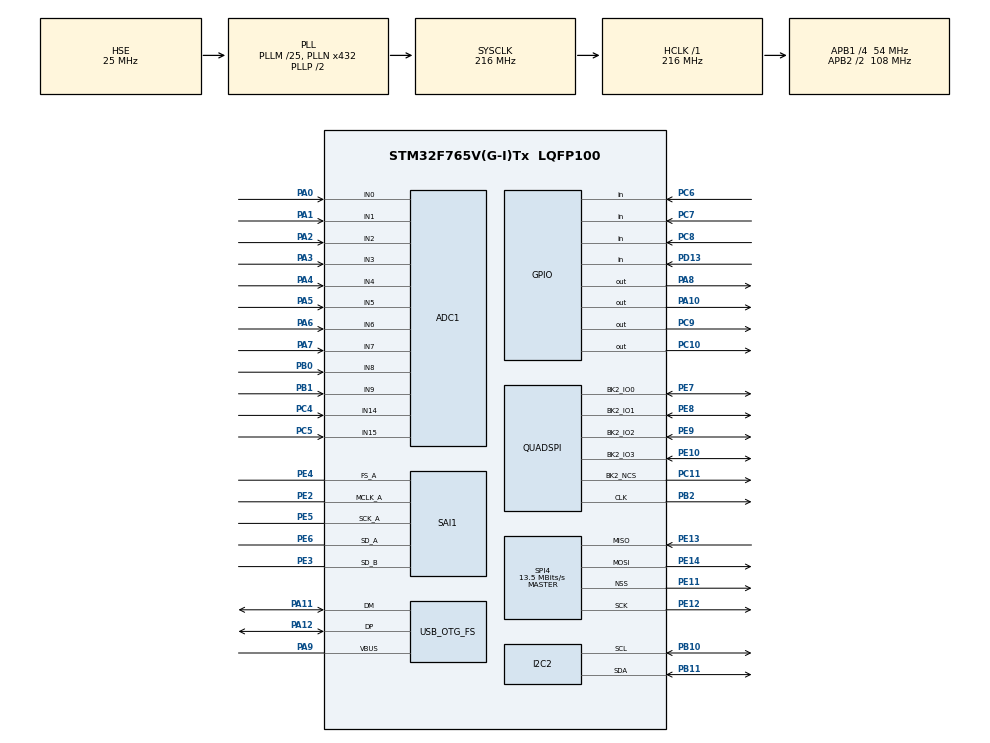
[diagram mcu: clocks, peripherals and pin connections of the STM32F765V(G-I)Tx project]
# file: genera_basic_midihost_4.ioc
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ADC1.Channel-0\#ChannelRegularConversion=ADC_CHANNEL_9
ADC1.Channel-1\#ChannelRegularConversion=ADC_CHANNEL_8
ADC1.Channel-10\#ChannelRegularConversion=ADC_CHANNEL_3
ADC1.Channel-11\#ChannelRegularConversion=ADC_CHANNEL_2
ADC1.Channel-2\#ChannelRegularConversion=ADC_CHANNEL_15
ADC1.Channel-3\#ChannelRegularConversion=ADC_CHANNEL_14
ADC1.Channel-4\#ChannelRegularConversion=ADC_CHANNEL_1
ADC1.Channel-5\#ChannelRegularConversion=ADC_CHANNEL_0
ADC1.Channel-6\#ChannelRegularConversion=ADC_CHANNEL_5
ADC1.Channel-7\#ChannelRegularConversion=ADC_CHANNEL_4
ADC1.Channel-8\#ChannelRegularConversion=ADC_CHANNEL_7
ADC1.Channel-9\#ChannelRegularConversion=ADC_CHANNEL_6
ADC1.ContinuousConvMode=ENABLE
ADC1.ExternalTrigConv=ADC_EXTERNALTRIGCONV_T1_CC1
ADC1.NbrOfConversion=12
ADC1.NbrOfConversionFlag=1
ADC1.Rank-0\#ChannelRegularConversion=1
ADC1.Rank-1\#ChannelRegularConversion=2
ADC1.Rank-10\#ChannelRegularConversion=11
ADC1.Rank-11\#ChannelRegularConversion=12
ADC1.Rank-2\#ChannelRegularConversion=3
ADC1.Rank-3\#ChannelRegularConversion=4
ADC1.Rank-4\#ChannelRegularConversion=5
ADC1.Rank-5\#ChannelRegularConversion=6
ADC1.Rank-6\#ChannelRegularConversion=7
ADC1.Rank-7\#ChannelRegularConversion=8
ADC1.Rank-8\#ChannelRegularConversion=9
ADC1.Rank-9\#ChannelRegularConversion=10
ADC1.SamplingTime-0\#ChannelRegularConversion=ADC_SAMPLETIME_3CYCLES
ADC1.SamplingTime-1\#ChannelRegularConversion=ADC_SAMPLETIME_3CYCLES
ADC1.SamplingTime-10\#ChannelRegularConversion=ADC_SAMPLETIME_3CYCLES
ADC1.SamplingTime-11\#ChannelRegularConversion=ADC_SAMPLETIME_3CYCLES
ADC1.SamplingTime-2\#ChannelRegularConversion=ADC_SAMPLETIME_3CYCLES
ADC1.SamplingTime-3\#ChannelRegularConversion=ADC_SAMPLETIME_3CYCLES
ADC1.SamplingTime-4\#ChannelRegularConversion=ADC_SAMPLETIME_3CYCLES
ADC1.SamplingTime-5\#ChannelRegularConversion=ADC_SAMPLETIME_3CYCLES
ADC1.SamplingTime-6\#ChannelRegularConversion=ADC_SAMPLETIME_3CYCLES
ADC1.SamplingTime-7\#ChannelRegularConversion=ADC_SAMPLETIME_3CYCLES
ADC1.SamplingTime-8\#ChannelRegularConversion=ADC_SAMPLETIME_3CYCLES
ADC1.SamplingTime-9\#ChannelRegularConversion=ADC_SAMPLETIME_3CYCLES
ADC1.master=1
Dma.ADC1.4.Direction=DMA_PERIPH_TO_MEMORY
Dma.ADC1.4.FIFOMode=DMA_FIFOMODE_DISABLE
Dma.ADC1.4.Instance=DMA2_Stream4
Dma.ADC1.4.MemDataAlignment=DMA_MDATAALIGN_HALFWORD
Dma.ADC1.4.MemInc=DMA_MINC_ENABLE
Dma.ADC1.4.Mode=DMA_NORMAL
Dma.ADC1.4.PeriphDataAlignment=DMA_PDATAALIGN_HALFWORD
Dma.ADC1.4.PeriphInc=DMA_PINC_DISABLE
Dma.ADC1.4.Priority=DMA_PRIORITY_LOW
Dma.I2C2_RX.2.Direction=DMA_PERIPH_TO_MEMORY
Dma.I2C2_RX.2.FIFOMode=DMA_FIFOMODE_DISABLE
Dma.I2C2_RX.2.Instance=DMA1_Stream2
Dma.I2C2_RX.2.MemDataAlignment=DMA_MDATAALIGN_BYTE
Dma.I2C2_RX.2.MemInc=DMA_MINC_ENABLE
Dma.I2C2_RX.2.Mode=DMA_NORMAL
Dma.I2C2_RX.2.PeriphDataAlignment=DMA_PDATAALIGN_BYTE
Dma.I2C2_RX.2.PeriphInc=DMA_PINC_DISABLE
Dma.I2C2_RX.2.Priority=DMA_PRIORITY_LOW
Dma.I2C2_TX.3.Direction=DMA_MEMORY_TO_PERIPH
Dma.I2C2_TX.3.FIFOMode=DMA_FIFOMODE_DISABLE
Dma.I2C2_TX.3.Instance=DMA1_Stream4
Dma.I2C2_TX.3.MemDataAlignment=DMA_MDATAALIGN_BYTE
Dma.I2C2_TX.3.MemInc=DMA_MINC_ENABLE
Dma.I2C2_TX.3.Mode=DMA_NORMAL
Dma.I2C2_TX.3.PeriphDataAlignment=DMA_PDATAALIGN_BYTE
Dma.I2C2_TX.3.PeriphInc=DMA_PINC_DISABLE
Dma.I2C2_TX.3.Priority=DMA_PRIORITY_LOW
Dma.Request0=SAI1_A
Dma.Request1=SAI1_B
Dma.Request2=I2C2_RX
Dma.Request3=I2C2_TX
Dma.Request4=ADC1
Dma.SAI1_A.0.Direction=DMA_MEMORY_TO_PERIPH
Dma.SAI1_A.0.FIFOMode=DMA_FIFOMODE_ENABLE
Dma.SAI1_A.0.FIFOThreshold=DMA_FIFO_THRESHOLD_FULL
Dma.SAI1_A.0.Instance=DMA2_Stream1
Dma.SAI1_A.0.MemBurst=DMA_MBURST_SINGLE
Dma.SAI1_A.0.MemDataAlignment=DMA_MDATAALIGN_HALFWORD
Dma.SAI1_A.0.MemInc=DMA_MINC_ENABLE
Dma.SAI1_A.0.Mode=DMA_CIRCULAR
Dma.SAI1_A.0.PeriphBurst=DMA_PBURST_SINGLE
Dma.SAI1_A.0.PeriphDataAlignment=DMA_PDATAALIGN_HALFWORD
Dma.SAI1_A.0.PeriphInc=DMA_PINC_DISABLE
Dma.SAI1_A.0.Priority=DMA_PRIORITY_HIGH
Dma.SAI1_B.1.Direction=DMA_PERIPH_TO_MEMORY
Dma.SAI1_B.1.FIFOMode=DMA_FIFOMODE_ENABLE
Dma.SAI1_B.1.FIFOThreshold=DMA_FIFO_THRESHOLD_FULL
Dma.SAI1_B.1.Instance=DMA2_Stream0
Dma.SAI1_B.1.MemBurst=DMA_MBURST_SINGLE
Dma.SAI1_B.1.MemDataAlignment=DMA_MDATAALIGN_HALFWORD
Dma.SAI1_B.1.MemInc=DMA_MINC_ENABLE
Dma.SAI1_B.1.Mode=DMA_CIRCULAR
Dma.SAI1_B.1.PeriphBurst=DMA_PBURST_SINGLE
Dma.SAI1_B.1.PeriphDataAlignment=DMA_PDATAALIGN_HALFWORD
Dma.SAI1_B.1.PeriphInc=DMA_PINC_DISABLE
Dma.SAI1_B.1.Priority=DMA_PRIORITY_HIGH
I2C2.Timing=0x20404768
Mcu.Family=STM32F7
Mcu.Name=STM32F765V(G-I)Tx
Mcu.Package=LQFP100
NVIC.DMA1_Stream2_IRQn=true\:0\:0\:false\:false\:true
NVIC.DMA1_Stream4_IRQn=true\:0\:0\:false\:false\:true
NVIC.DMA2_Stream0_IRQn=true\:0\:0\:false\:false\:true
NVIC.DMA2_Stream1_IRQn=true\:0\:0\:false\:false\:true
NVIC.DMA2_Stream4_IRQn=true\:0\:0\:false\:false\:true
NVIC.OTG_FS_IRQn=true\:0\:0\:false\:false\:true
NVIC.PriorityGroup=NVIC_PRIORITYGROUP_4
PA0/WKUP.Signal=ADCx_IN0
PA1.Signal=ADCx_IN1
PA10.Signal=GPIO_Output
PA11.Mode=Host_Only
PA11.Signal=USB_OTG_FS_DM
PA12.Mode=Host_Only
PA12.Signal=USB_OTG_FS_DP
PA2.Signal=ADCx_IN2
PA3.Signal=ADCx_IN3
PA4.Signal=ADCx_IN4
PA5.Signal=ADCx_IN5
PA6.Signal=ADCx_IN6
PA7.Signal=ADCx_IN7
PA8.Signal=GPIO_Output
PA9.Mode=Activate_VBUS
PA9.Signal=USB_OTG_FS_VBUS
PB0.Signal=ADCx_IN8
PB1.Signal=ADCx_IN9
PB10.Mode=I2C
PB10.Signal=I2C2_SCL
PB11.Mode=I2C
PB11.Signal=I2C2_SDA
PB2.Mode=Single Bank 2
PB2.Signal=QUADSPI_CLK
PC10.Signal=GPIO_Output
PC11.Mode=Single Bank 2
PC11.Signal=QUADSPI_BK2_NCS
PC4.Signal=ADCx_IN14
PC5.Signal=ADCx_IN15
PC6.Signal=GPIO_Input
PC7.Signal=GPIO_Input
PC8.Signal=GPIO_Input
PC9.Signal=GPIO_Output
PD13.Signal=GPIO_Input
PE10.Mode=Single Bank 2
PE10.Signal=QUADSPI_BK2_IO3
PE11.Mode=NSS_Signal_Hard_Output
PE11.Signal=SPI4_NSS
PE12.Mode=Full_Duplex_Master
PE12.Signal=SPI4_SCK
PE13.Mode=Full_Duplex_Master
PE13.Signal=SPI4_MISO
PE14.Mode=Full_Duplex_Master
PE14.Signal=SPI4_MOSI
PE2.Mode=SAI_A_MasterWithClock
PE2.Signal=SAI1_MCLK_A
PE3.Mode=SAI_B_SyncSlave
PE3.Signal=SAI1_SD_B
PE4.Mode=SAI_A_MasterWithClock
PE4.Signal=SAI1_FS_A
PE5.Mode=SAI_A_MasterWithClock
PE5.Signal=SAI1_SCK_A
PE6.Mode=SAI_A_MasterWithClock
PE6.Signal=SAI1_SD_A
PE7.Mode=Single Bank 2
PE7.Signal=QUADSPI_BK2_IO0
PE8.Mode=Single Bank 2
PE8.Signal=QUADSPI_BK2_IO1
PE9.Mode=Single Bank 2
PE9.Signal=QUADSPI_BK2_IO2
PH0/OSC_IN.Mode=HSE-External-Oscillator
PH0/OSC_IN.Signal=RCC_OSC_IN
PH1/OSC_OUT.Mode=HSE-External-Oscillator
PH1/OSC_OUT.Signal=RCC_OSC_OUT
ProjectManager.HeapSize=0x200
ProjectManager.StackSize=0x400
ProjectManager.TargetToolchain=MDK-ARM V5
RCC.AHBFreq_Value=216000000
RCC.APB1CLKDivider=RCC_HCLK_DIV4
RCC.APB1Freq_Value=54000000
RCC.APB1TimFreq_Value=108000000
RCC.APB2CLKDivider=RCC_HCLK_DIV2
RCC.APB2Freq_Value=108000000
RCC.APB2TimFreq_Value=216000000
RCC.CortexFreq_Value=216000000
RCC.HCLKFreq_Value=216000000
RCC.HSE_VALUE=25000000
RCC.HSI_VALUE=16000000
RCC.LSE_VALUE=32768
RCC.PLLI2SN=344
RCC.PLLI2SQ=7
RCC.PLLM=25
RCC.PLLN=432
RCC.PLLQ=9
RCC.PLLSAIN=376
RCC.PLLSAIQ=9
RCC.SAI1CLockSelection=RCC_SAI1CLKSOURCE_PLLI2S
RCC.SYSCLKFreq_VALUE=216000000
RCC.SYSCLKSource=RCC_SYSCLKSOURCE_PLLCLK
RCC.USBFreq_Value=48000000
RCC.VCOOutputFreq_Value=432000000
SAI1.ErrorAudioFreq-SAI_A_MasterWithClock=-0.01 %
SAI1.InitProtocol-SAI_A_MasterWithClock=Enable
SAI1.InitProtocol-SAI_B_SyncSlave=Enable
SAI1.Instance-SAI_A_MasterWithClock=SAI$Index_Block_A
SAI1.Instance-SAI_B_SyncSlave=SAI$Index_Block_B
SAI1.MClockEnable=SAI_MASTERCLOCK_ENABLE
SAI1.RealAudioFreq-SAI_A_MasterWithClock=191.964 KHz
SAI1.Synchro-SAI_A_MasterWithClock=SAI_ASYNCHRONOUS
SAI1.Synchro-SAI_B_SyncSlave=SAI_SYNCHRONOUS
SAI1.VirtualMode-SAI_A_MasterWithClock=VM_MASTER
SAI1.VirtualMode-SAI_B_SyncSlave=VM_SLAVE
SAI1.VirtualProtocol-SAI_A_BASIC=VM_BASIC_PROTOCOL
SAI1.VirtualProtocol-SAI_B_BASIC=VM_BASIC_PROTOCOL
SH.ADCx_IN0.0=ADC1_IN0,IN0
SH.ADCx_IN1.0=ADC1_IN1,IN1
SH.ADCx_IN14.0=ADC1_IN14,IN14
SH.ADCx_IN15.0=ADC1_IN15,IN15
SH.ADCx_IN2.0=ADC1_IN2,IN2
SH.ADCx_IN3.0=ADC1_IN3,IN3
SH.ADCx_IN4.0=ADC1_IN4,IN4
SH.ADCx_IN5.0=ADC1_IN5,IN5
SH.ADCx_IN6.0=ADC1_IN6,IN6
SH.ADCx_IN7.0=ADC1_IN7,IN7
SH.ADCx_IN8.0=ADC1_IN8,IN8
SH.ADCx_IN9.0=ADC1_IN9,IN9
SPI4.BaudRatePrescaler=SPI_BAUDRATEPRESCALER_8
SPI4.CalculateBaudRate=13.5 MBits/s
SPI4.Direction=SPI_DIRECTION_2LINES
SPI4.Mode=SPI_MODE_MASTER
SPI4.VirtualNSS=VM_NSSHARD
SPI4.VirtualType=VM_MASTER
USB_HOST.USBH_HandleTypeDef-AUDIO_FS=hUsbHostFS
USB_HOST.VirtualModeFS=Audio
USB_OTG_FS.VirtualMode=Host_Only
USB_OTG_FS.phy_itface=HCD_PHY_EMBEDDED
VP_RNG_VS_RNG.Mode=RNG_Activate
VP_SAI1_VP_$IpInstance_SAIA_SAI_BASIC.Mode=SAI_A_BASIC
VP_SAI1_VP_$IpInstance_SAIB_SAI_BASIC.Mode=SAI_B_BASIC
VP_USB_HOST_VS_USB_HOST_AUDIO_FS.Mode=AUDIO_FS
board=genera_basic_midihost_4

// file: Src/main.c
/**
  ******************************************************************************
  * File Name          : main.c
  * Description        : Main program body
  ******************************************************************************
  *
  * Copyright (c) 2017 STMicroelectronics International N.V.
  * All rights reserved.
  *
  * Redistribution and use in source and binary forms, with or without
  * modification, are permitted, provided that the following conditions are met:
  *
  * 1. Redistribution of source code must retain the above copyright notice,
  *    this list of conditions and the following disclaimer.
  * 2. Redistributions in binary form must reproduce the above copyright notice,
  *    this list of conditions and the following disclaimer in the documentation
  *    and/or other materials provided with the distribution.
  * 3. Neither the name of STMicroelectronics nor the names of other
  *    contributors to this software may be used to endorse or promote products
  *    derived from this software without specific written permission.
  * 4. This software, including modifications and/or derivative works of this
  *    software, must execute solely and exclusively on microcontroller or
  *    microprocessor devices manufactured by or for STMicroelectronics.
  * 5. Redistribution and use of this software other than as permitted under
  *    this license is void and will automatically terminate your rights under
  *    this license.
  *
  * THIS SOFTWARE IS PROVIDED BY STMICROELECTRONICS AND CONTRIBUTORS "AS IS"
  * AND ANY EXPRESS, IMPLIED OR STATUTORY WARRANTIES, INCLUDING, BUT NOT
  * LIMITED TO, THE IMPLIED WARRANTIES OF MERCHANTABILITY, FITNESS FOR A
  * PARTICULAR PURPOSE AND NON-INFRINGEMENT OF THIRD PARTY INTELLECTUAL PROPERTY
  * RIGHTS ARE DISCLAIMED TO THE FULLEST EXTENT PERMITTED BY LAW. IN NO EVENT
  * SHALL STMICROELECTRONICS OR CONTRIBUTORS BE LIABLE FOR ANY DIRECT, INDIRECT,
  * INCIDENTAL, SPECIAL, EXEMPLARY, OR CONSEQUENTIAL DAMAGES (INCLUDING, BUT NOT
  * LIMITED TO, PROCUREMENT OF SUBSTITUTE GOODS OR SERVICES; LOSS OF USE, DATA,
  * OR PROFITS; OR BUSINESS INTERRUPTION) HOWEVER CAUSED AND ON ANY THEORY OF
  * LIABILITY, WHETHER IN CONTRACT, STRICT LIABILITY, OR TORT (INCLUDING
  * NEGLIGENCE OR OTHERWISE) ARISING IN ANY WAY OUT OF THE USE OF THIS SOFTWARE,
  * EVEN IF ADVISED OF THE POSSIBILITY OF SUCH DAMAGE.
  *
  ******************************************************************************
  */
#include "main.h"
#include "stm32f7xx_hal.h"
#include "usb_host.h"

#include "audiostream.h"
#include "codec.h"
#include "OOPSMath.h"

ADC_HandleTypeDef hadc1;
DMA_HandleTypeDef hdma_adc1;

I2C_HandleTypeDef hi2c2;
DMA_HandleTypeDef hdma_i2c2_rx;
DMA_HandleTypeDef hdma_i2c2_tx;

QSPI_HandleTypeDef hqspi;

RNG_HandleTypeDef hrng;

SAI_HandleTypeDef hsai_BlockA1;
SAI_HandleTypeDef hsai_BlockB1;
DMA_HandleTypeDef hdma_sai1_a;
DMA_HandleTypeDef hdma_sai1_b;

SPI_HandleTypeDef hspi4;

/* USER CODE BEGIN PV */
/* Private variables ---------------------------------------------------------*/

/* USER CODE END PV */

void SystemClock_Config(void);
void Error_Handler(void);
static void MX_GPIO_Init(void);
static void MX_DMA_Init(void);
static void MX_ADC1_Init(void);
static void MX_I2C2_Init(void);
static void MX_QUADSPI_Init(void);
static void MX_RNG_Init(void);
static void MX_SAI1_Init(void);
static void MX_SPI4_Init(void);
void MX_USB_HOST_Process(void);

#define NUM_ADC_CHANNELS 12

__IO uint16_t adcValues[NUM_ADC_CHANNELS];
uint16_t whichADC = 0;
uint16_t test = 0;

uint8_t SPI_data_in[3] = {0, 0, 0};
uint8_t SPI_data_out[3] = {0, 0, 0};
long ADC16Value = 0;

int main(void)
{

  /* Reset of all peripherals, Initializes the Flash interface and the Systick. */
  HAL_Init();

  /* Configure the system clock */
  SystemClock_Config();

  /* Initialize all configured peripherals */
  MX_GPIO_Init();
  MX_DMA_Init();
  MX_ADC1_Init();
  MX_I2C2_Init();
  MX_QUADSPI_Init();
  MX_RNG_Init();
  MX_SAI1_Init();
  MX_SPI4_Init();
  MX_USB_HOST_Init();

	if (HAL_ADC_Start_DMA(&hadc1,(uint32_t*)&adcValues, NUM_ADC_CHANNELS) != HAL_OK)
	{
		Error_Handler();
	}

	audioInit(&hi2c2, &hsai_BlockA1, &hsai_BlockB1, &hrng, ((uint16_t*)&adcValues));

  while (1)
  {
    MX_USB_HOST_Process();

  }

}

/** System Clock Configuration
*/
void SystemClock_Config(void)
{

  RCC_OscInitTypeDef RCC_OscInitStruct;
  RCC_ClkInitTypeDef RCC_ClkInitStruct;
  RCC_PeriphCLKInitTypeDef PeriphClkInitStruct;

    /**Configure the main internal regulator output voltage
    */
  __HAL_RCC_PWR_CLK_ENABLE();

  __HAL_PWR_VOLTAGESCALING_CONFIG(PWR_REGULATOR_VOLTAGE_SCALE1);

    /**Initializes the CPU, AHB and APB busses clocks
    */
  RCC_OscInitStruct.OscillatorType = RCC_OSCILLATORTYPE_HSE;
  RCC_OscInitStruct.HSEState = RCC_HSE_ON;
  RCC_OscInitStruct.PLL.PLLState = RCC_PLL_ON;
  RCC_OscInitStruct.PLL.PLLSource = RCC_PLLSOURCE_HSE;
  RCC_OscInitStruct.PLL.PLLM = 25;
  RCC_OscInitStruct.PLL.PLLN = 432;
  RCC_OscInitStruct.PLL.PLLP = RCC_PLLP_DIV2;
  RCC_OscInitStruct.PLL.PLLQ = 9;
  if (HAL_RCC_OscConfig(&RCC_OscInitStruct) != HAL_OK)
  {
    Error_Handler();
  }

    /**Activate the Over-Drive mode
    */
  if (HAL_PWREx_EnableOverDrive() != HAL_OK)
  {
    Error_Handler();
  }

    /**Initializes the CPU, AHB and APB busses clocks
    */
  RCC_ClkInitStruct.ClockType = RCC_CLOCKTYPE_HCLK|RCC_CLOCKTYPE_SYSCLK
                              |RCC_CLOCKTYPE_PCLK1|RCC_CLOCKTYPE_PCLK2;
  RCC_ClkInitStruct.SYSCLKSource = RCC_SYSCLKSOURCE_PLLCLK;
  RCC_ClkInitStruct.AHBCLKDivider = RCC_SYSCLK_DIV1;
  RCC_ClkInitStruct.APB1CLKDivider = RCC_HCLK_DIV4;
  RCC_ClkInitStruct.APB2CLKDivider = RCC_HCLK_DIV2;

  if (HAL_RCC_ClockConfig(&RCC_ClkInitStruct, FLASH_LATENCY_7) != HAL_OK)
  {
    Error_Handler();
  }

  PeriphClkInitStruct.PeriphClockSelection = RCC_PERIPHCLK_SAI1|RCC_PERIPHCLK_I2C2
                              |RCC_PERIPHCLK_CLK48;
  PeriphClkInitStruct.PLLI2S.PLLI2SN = 344;
  PeriphClkInitStruct.PLLI2S.PLLI2SP = RCC_PLLP_DIV2;
  PeriphClkInitStruct.PLLI2S.PLLI2SR = 2;
  PeriphClkInitStruct.PLLI2S.PLLI2SQ = 7;
  PeriphClkInitStruct.PLLI2SDivQ = 1;
  PeriphClkInitStruct.Sai1ClockSelection = RCC_SAI1CLKSOURCE_PLLI2S;
  PeriphClkInitStruct.I2c2ClockSelection = RCC_I2C2CLKSOURCE_PCLK1;
  PeriphClkInitStruct.Clk48ClockSelection = RCC_CLK48SOURCE_PLL;
  if (HAL_RCCEx_PeriphCLKConfig(&PeriphClkInitStruct) != HAL_OK)
  {
    Error_Handler();
  }

    /**Configure the Systick interrupt time
    */
  HAL_SYSTICK_Config(HAL_RCC_GetHCLKFreq()/1000);

    /**Configure the Systick
    */
  HAL_SYSTICK_CLKSourceConfig(SYSTICK_CLKSOURCE_HCLK);

  /* SysTick_IRQn interrupt configuration */
  HAL_NVIC_SetPriority(SysTick_IRQn, 0, 0);
}

/* ADC1 init function */
static void MX_ADC1_Init(void)
{
 ADC_ChannelConfTypeDef sConfig;

    /**Configure the global features of the ADC (Clock, Resolution, Data Alignment and number of conversion)
    */
  hadc1.Instance = ADC1;
  hadc1.Init.ClockPrescaler = ADC_CLOCK_SYNC_PCLK_DIV8;
  hadc1.Init.Resolution = ADC_RESOLUTION_12B;
  hadc1.Init.ScanConvMode = ENABLE;
  hadc1.Init.ContinuousConvMode = ENABLE;
  hadc1.Init.DiscontinuousConvMode = DISABLE;
  hadc1.Init.ExternalTrigConvEdge = ADC_EXTERNALTRIGCONVEDGE_NONE;
  hadc1.Init.ExternalTrigConv = ADC_SOFTWARE_START;
  hadc1.Init.DataAlign = ADC_DATAALIGN_RIGHT;
  hadc1.Init.NbrOfConversion = NUM_ADC_CHANNELS;
  hadc1.Init.DMAContinuousRequests = ENABLE;
  hadc1.Init.EOCSelection = DISABLE;

  if (HAL_ADC_Init(&hadc1) != HAL_OK)
  {
    Error_Handler();
  }

    /**Configure for the selected ADC regular channel its corresponding rank in the sequencer and its sample time.
    */
  sConfig.Channel = ADC_CHANNEL_0;
  sConfig.Rank = 1;
  sConfig.SamplingTime = ADC_SAMPLETIME_480CYCLES;

  if (HAL_ADC_ConfigChannel(&hadc1, &sConfig) != HAL_OK)
  {
    Error_Handler();
  }

    /**Configure for the selected ADC regular channel its corresponding rank in the sequencer and its sample time.
    */
  sConfig.Channel = ADC_CHANNEL_1;
  sConfig.Rank = 2;
  if (HAL_ADC_ConfigChannel(&hadc1, &sConfig) != HAL_OK)
  {
    Error_Handler();
  }

    /**Configure for the selected ADC regular channel its corresponding rank in the sequencer and its sample time.
    */
  sConfig.Channel = ADC_CHANNEL_2;
  sConfig.Rank = 3;
  if (HAL_ADC_ConfigChannel(&hadc1, &sConfig) != HAL_OK)
  {
    Error_Handler();
  }

    /**Configure for the selected ADC regular channel its corresponding rank in the sequencer and its sample time.
    */
  sConfig.Channel = ADC_CHANNEL_3;
  sConfig.Rank = 4;
  if (HAL_ADC_ConfigChannel(&hadc1, &sConfig) != HAL_OK)
  {
    Error_Handler();
  }

  sConfig.Channel = ADC_CHANNEL_4;
  sConfig.Rank = 5;
  if (HAL_ADC_ConfigChannel(&hadc1, &sConfig) != HAL_OK)
  {
    Error_Handler();
  }

}

/* I2C2 init function */
static void MX_I2C2_Init(void)
{

  hi2c2.Instance = I2C2;
  hi2c2.Init.Timing = 0x20404768;
  hi2c2.Init.OwnAddress1 = 0;
  hi2c2.Init.AddressingMode = I2C_ADDRESSINGMODE_7BIT;
  hi2c2.Init.DualAddressMode = I2C_DUALADDRESS_DISABLE;
  hi2c2.Init.OwnAddress2 = 0;
  hi2c2.Init.OwnAddress2Masks = I2C_OA2_NOMASK;
  hi2c2.Init.GeneralCallMode = I2C_GENERALCALL_DISABLE;
  hi2c2.Init.NoStretchMode = I2C_NOSTRETCH_DISABLE;
  if (HAL_I2C_Init(&hi2c2) != HAL_OK)
  {
    Error_Handler();
  }

    /**Configure Analogue filter
    */
  if (HAL_I2CEx_ConfigAnalogFilter(&hi2c2, I2C_ANALOGFILTER_ENABLE) != HAL_OK)
  {
    Error_Handler();
  }

}

/* QUADSPI init function */
static void MX_QUADSPI_Init(void)
{

  hqspi.Instance = QUADSPI;
  hqspi.Init.ClockPrescaler = 255;
  hqspi.Init.FifoThreshold = 1;
  hqspi.Init.SampleShifting = QSPI_SAMPLE_SHIFTING_NONE;
  hqspi.Init.FlashSize = 1;
  hqspi.Init.ChipSelectHighTime = QSPI_CS_HIGH_TIME_1_CYCLE;
  hqspi.Init.ClockMode = QSPI_CLOCK_MODE_0;
  hqspi.Init.FlashID = QSPI_FLASH_ID_2;
  hqspi.Init.DualFlash = QSPI_DUALFLASH_DISABLE;
  if (HAL_QSPI_Init(&hqspi) != HAL_OK)
  {
    Error_Handler();
  }

}

/* RNG init function */
static void MX_RNG_Init(void)
{

  hrng.Instance = RNG;
  if (HAL_RNG_Init(&hrng) != HAL_OK)
  {
    Error_Handler();
  }

}

/* SAI1 init function */
static void MX_SAI1_Init(void)
{

  hsai_BlockA1.Instance = SAI1_Block_A;
  hsai_BlockA1.Init.AudioMode = SAI_MODEMASTER_TX;
  hsai_BlockA1.Init.Synchro = SAI_ASYNCHRONOUS;
  hsai_BlockA1.Init.OutputDrive = SAI_OUTPUTDRIVE_DISABLE;
  hsai_BlockA1.Init.NoDivider = SAI_MASTERDIVIDER_ENABLE;
  hsai_BlockA1.Init.FIFOThreshold = SAI_FIFOTHRESHOLD_EMPTY;
  hsai_BlockA1.Init.AudioFrequency = SAI_AUDIO_FREQUENCY_48K;
  hsai_BlockA1.Init.SynchroExt = SAI_SYNCEXT_DISABLE;
  hsai_BlockA1.Init.MonoStereoMode = SAI_STEREOMODE;
  hsai_BlockA1.Init.CompandingMode = SAI_NOCOMPANDING;
  hsai_BlockA1.Init.TriState = SAI_OUTPUT_NOTRELEASED;
  if (HAL_SAI_InitProtocol(&hsai_BlockA1, SAI_I2S_STANDARD, SAI_PROTOCOL_DATASIZE_16BIT, 2) != HAL_OK)
  {
    Error_Handler();
  }

  hsai_BlockB1.Instance = SAI1_Block_B;
  hsai_BlockB1.Init.AudioMode = SAI_MODESLAVE_RX;
  hsai_BlockB1.Init.Synchro = SAI_SYNCHRONOUS;
  hsai_BlockB1.Init.OutputDrive = SAI_OUTPUTDRIVE_DISABLE;
  hsai_BlockB1.Init.FIFOThreshold = SAI_FIFOTHRESHOLD_EMPTY;
  hsai_BlockB1.Init.SynchroExt = SAI_SYNCEXT_DISABLE;
  hsai_BlockB1.Init.MonoStereoMode = SAI_STEREOMODE;
  hsai_BlockB1.Init.CompandingMode = SAI_NOCOMPANDING;
  hsai_BlockB1.Init.TriState = SAI_OUTPUT_NOTRELEASED;
  if (HAL_SAI_InitProtocol(&hsai_BlockB1, SAI_I2S_STANDARD, SAI_PROTOCOL_DATASIZE_16BIT, 2) != HAL_OK)
  {
    Error_Handler();
  }

}

/* SPI4 init function */
static void MX_SPI4_Init(void)
{

  hspi4.Instance = SPI4;
  hspi4.Init.Mode = SPI_MODE_MASTER;
  hspi4.Init.Direction = SPI_DIRECTION_2LINES;
  hspi4.Init.DataSize = SPI_DATASIZE_8BIT;
  hspi4.Init.CLKPolarity = SPI_POLARITY_HIGH;
  hspi4.Init.CLKPhase = SPI_PHASE_1EDGE;
  hspi4.Init.NSS = SPI_NSS_SOFT;
  hspi4.Init.BaudRatePrescaler = SPI_BAUDRATEPRESCALER_256;
  hspi4.Init.FirstBit = SPI_FIRSTBIT_MSB;
  hspi4.Init.TIMode = SPI_TIMODE_DISABLE;
  hspi4.Init.CRCCalculation = SPI_CRCCALCULATION_DISABLE;
  hspi4.Init.CRCPolynomial = 7;
  hspi4.Init.CRCLength = SPI_CRC_LENGTH_DATASIZE;
  hspi4.Init.NSSPMode = SPI_NSS_PULSE_DISABLE;
  if (HAL_SPI_Init(&hspi4) != HAL_OK)
  {
    Error_Handler();
  }

}

static void MX_DMA_Init(void)
{
  /* DMA controller clock enable */
  __HAL_RCC_DMA2_CLK_ENABLE();
  __HAL_RCC_DMA1_CLK_ENABLE();

  /* DMA interrupt init */
  /* DMA1_Stream2_IRQn interrupt configuration */
  HAL_NVIC_SetPriority(DMA1_Stream2_IRQn, 0, 0);
  HAL_NVIC_EnableIRQ(DMA1_Stream2_IRQn);
  /* DMA1_Stream4_IRQn interrupt configuration */
  HAL_NVIC_SetPriority(DMA1_Stream4_IRQn, 0, 0);
  HAL_NVIC_EnableIRQ(DMA1_Stream4_IRQn);
  /* DMA2_Stream0_IRQn interrupt configuration */
  HAL_NVIC_SetPriority(DMA2_Stream0_IRQn, 0, 0);
  HAL_NVIC_EnableIRQ(DMA2_Stream0_IRQn);
  /* DMA2_Stream1_IRQn interrupt configuration */
  HAL_NVIC_SetPriority(DMA2_Stream1_IRQn, 0, 0);
  HAL_NVIC_EnableIRQ(DMA2_Stream1_IRQn);
  /* DMA2_Stream4_IRQn interrupt configuration */
  HAL_NVIC_SetPriority(DMA2_Stream4_IRQn, 0, 0);
  HAL_NVIC_EnableIRQ(DMA2_Stream4_IRQn);

}

/** Configure pins as
        * Analog
        * Input
        * Output
        * EVENT_OUT
        * EXTI
*/
static void MX_GPIO_Init(void)
{

  GPIO_InitTypeDef GPIO_InitStruct;

  /* GPIO Ports Clock Enable */
  __HAL_RCC_GPIOE_CLK_ENABLE();
  __HAL_RCC_GPIOH_CLK_ENABLE();
  __HAL_RCC_GPIOA_CLK_ENABLE();
  __HAL_RCC_GPIOC_CLK_ENABLE();
  __HAL_RCC_GPIOB_CLK_ENABLE();
  __HAL_RCC_GPIOD_CLK_ENABLE();

	#if 0

  /*Configure GPIO pin Output Level */
  HAL_GPIO_WritePin(GPIOC, GPIO_PIN_9|GPIO_PIN_10, GPIO_PIN_RESET);

  /*Configure GPIO pin Output Level */
  HAL_GPIO_WritePin(GPIOA, GPIO_PIN_8|GPIO_PIN_9|GPIO_PIN_10|GPIO_PIN_11
                          |GPIO_PIN_12, GPIO_PIN_RESET);

	/* ~ ~ ~ ~ ~ ~ ~ REMOVE THESE ? ~ ~ ~ ~ ~ ~ ~ ~ ~ */
  /*Configure GPIO pin : PD13 */
  GPIO_InitStruct.Pin = GPIO_PIN_13;
  GPIO_InitStruct.Mode = GPIO_MODE_INPUT;
  GPIO_InitStruct.Pull = GPIO_PULLDOWN;
  HAL_GPIO_Init(GPIOD, &GPIO_InitStruct);

	  /*Configure GPIO pin : PD11 */
  GPIO_InitStruct.Pin = GPIO_PIN_11;
  GPIO_InitStruct.Mode = GPIO_MODE_OUTPUT_PP;
  GPIO_InitStruct.Pull = GPIO_NOPULL;
  HAL_GPIO_Init(GPIOD, &GPIO_InitStruct);

	  /*Configure GPIO pin : PB13 */
		// if using Jack 5 as a digital input instead of an audio input
  GPIO_InitStruct.Pin = GPIO_PIN_13;
  GPIO_InitStruct.Mode = GPIO_MODE_INPUT;
  GPIO_InitStruct.Pull = GPIO_PULLDOWN;
  HAL_GPIO_Init(GPIOB, &GPIO_InitStruct);

  /*Configure GPIO pins : PC4 PC6 PC7 PC8 */
  GPIO_InitStruct.Pin = GPIO_PIN_4|GPIO_PIN_6|GPIO_PIN_8;
  GPIO_InitStruct.Mode = GPIO_MODE_INPUT;
  GPIO_InitStruct.Pull = GPIO_NOPULL;
  HAL_GPIO_Init(GPIOC, &GPIO_InitStruct);

	  /*Configure GPIO pins : PB0 PB1 */
  GPIO_InitStruct.Pin = GPIO_PIN_0|GPIO_PIN_1;
  GPIO_InitStruct.Mode = GPIO_MODE_INPUT;
  GPIO_InitStruct.Pull = GPIO_NOPULL;
  HAL_GPIO_Init(GPIOB, &GPIO_InitStruct);

  /*Configure GPIO pins : PC9 PC10 */
  GPIO_InitStruct.Pin = GPIO_PIN_10;
  GPIO_InitStruct.Mode = GPIO_MODE_OUTPUT_PP;
  GPIO_InitStruct.Pull = GPIO_NOPULL;
  GPIO_InitStruct.Speed = GPIO_SPEED_FREQ_LOW;
  HAL_GPIO_Init(GPIOC, &GPIO_InitStruct);

	 /*Configure GPIO pins : PB12 PB14 */
  GPIO_InitStruct.Pin = GPIO_PIN_12|GPIO_PIN_14;
  GPIO_InitStruct.Mode = GPIO_MODE_OUTPUT_PP;
  GPIO_InitStruct.Pull = GPIO_NOPULL;
  GPIO_InitStruct.Speed = GPIO_SPEED_FREQ_LOW;
  HAL_GPIO_Init(GPIOB, &GPIO_InitStruct);

  /*Configure GPIO pins : PA8 PA9 PA10 PA11
                           PA12 */
  GPIO_InitStruct.Pin = GPIO_PIN_8|GPIO_PIN_9|GPIO_PIN_10|GPIO_PIN_11
                          |GPIO_PIN_12;
  GPIO_InitStruct.Mode = GPIO_MODE_OUTPUT_PP;
  GPIO_InitStruct.Pull = GPIO_PULLUP;
  GPIO_InitStruct.Speed = GPIO_SPEED_FREQ_HIGH;
  HAL_GPIO_Init(GPIOA, &GPIO_InitStruct);
	/*! ~ ~ ~ ~ END REMOVE THESE?? ~ ~ ~ ~ */

	// OUR STUFF FOR VOCOBOX
	// ~ ~ ~ SWITCHES (low is switch position)
	  /*Configure GPIO pins : PA adc inputs */
  GPIO_InitStruct.Pin = GPIO_PIN_9;
  GPIO_InitStruct.Mode = GPIO_MODE_INPUT;
  GPIO_InitStruct.Pull = GPIO_PULLUP;
  HAL_GPIO_Init(GPIOA, &GPIO_InitStruct);

	  /*Configure GPIO pins : PC adc inputs */
  GPIO_InitStruct.Pin = GPIO_PIN_7 | GPIO_PIN_9;
  GPIO_InitStruct.Mode = GPIO_MODE_INPUT;
  GPIO_InitStruct.Pull = GPIO_PULLUP;
  HAL_GPIO_Init(GPIOC, &GPIO_InitStruct);

	  /*Configure GPIO pins : PD adc inputs */
  GPIO_InitStruct.Pin = GPIO_PIN_13;
  GPIO_InitStruct.Mode = GPIO_MODE_INPUT;
  GPIO_InitStruct.Pull = GPIO_PULLUP;
  HAL_GPIO_Init(GPIOD, &GPIO_InitStruct);
	//! ~ ~ ~ ~ ~ ~

	// ~ ~ ~ KNOBS + PEDAL
		// PA3 is CV , others are knobs
  GPIO_InitStruct.Pin = GPIO_PIN_0|GPIO_PIN_1|GPIO_PIN_2|GPIO_PIN_3|GPIO_PIN_4;
  GPIO_InitStruct.Mode = GPIO_MODE_INPUT;
  GPIO_InitStruct.Pull = GPIO_NOPULL;
  HAL_GPIO_Init(GPIOA, &GPIO_InitStruct);
	//! ~ ~ ~ ~ ~ ~

	// ~ ~ ~ ~ LEDS
	// PA7 (14) PC5 (15) PB1 (16)
	GPIO_InitStruct.Pin = GPIO_PIN_7;
  GPIO_InitStruct.Mode = GPIO_MODE_OUTPUT_PP;
  GPIO_InitStruct.Pull = GPIO_PULLUP;
  HAL_GPIO_Init(GPIOA, &GPIO_InitStruct);

	GPIO_InitStruct.Pin = GPIO_PIN_5;
  GPIO_InitStruct.Mode = GPIO_MODE_OUTPUT_PP;
  GPIO_InitStruct.Pull = GPIO_PULLUP;
  HAL_GPIO_Init(GPIOC, &GPIO_InitStruct);

	GPIO_InitStruct.Pin = GPIO_PIN_1;
  GPIO_InitStruct.Mode = GPIO_MODE_OUTPUT_PP;
  GPIO_InitStruct.Pull = GPIO_PULLUP;
  HAL_GPIO_Init(GPIOB, &GPIO_InitStruct);
	//! ~ ~ ~ ~ ~ ~

#endif

	/** Configure pins as
        * Analog
        * Input
        * Output
        * EVENT_OUT
        * EXTI
*/
  /* GPIO Ports Clock Enable */
  __HAL_RCC_GPIOE_CLK_ENABLE();
  __HAL_RCC_GPIOH_CLK_ENABLE();
  __HAL_RCC_GPIOA_CLK_ENABLE();
  __HAL_RCC_GPIOC_CLK_ENABLE();
  __HAL_RCC_GPIOB_CLK_ENABLE();
  __HAL_RCC_GPIOD_CLK_ENABLE();

  /*Configure GPIO pin Output Level */
  HAL_GPIO_WritePin(GPIOC, GPIO_PIN_9|GPIO_PIN_10, GPIO_PIN_RESET);

  /*Configure GPIO pin Output Level */
  HAL_GPIO_WritePin(GPIOA, GPIO_PIN_8|GPIO_PIN_10, GPIO_PIN_RESET);

  /*Configure GPIO pin : PD13 */
  GPIO_InitStruct.Pin = GPIO_PIN_13;
  GPIO_InitStruct.Mode = GPIO_MODE_INPUT;
  GPIO_InitStruct.Pull = GPIO_NOPULL;
  HAL_GPIO_Init(GPIOD, &GPIO_InitStruct);

  /*Configure GPIO pins : PC6 PC7 PC8 */
  GPIO_InitStruct.Pin = GPIO_PIN_6|GPIO_PIN_7|GPIO_PIN_8;
  GPIO_InitStruct.Mode = GPIO_MODE_INPUT;
  GPIO_InitStruct.Pull = GPIO_NOPULL;
  HAL_GPIO_Init(GPIOC, &GPIO_InitStruct);

  /*Configure GPIO pins : PC9 PC10 */
  GPIO_InitStruct.Pin = GPIO_PIN_9|GPIO_PIN_10;
  GPIO_InitStruct.Mode = GPIO_MODE_OUTPUT_PP;
  GPIO_InitStruct.Pull = GPIO_NOPULL;
  GPIO_InitStruct.Speed = GPIO_SPEED_FREQ_LOW;
  HAL_GPIO_Init(GPIOC, &GPIO_InitStruct);

  /*Configure GPIO pins : PA8 PA10 */
  GPIO_InitStruct.Pin = GPIO_PIN_8|GPIO_PIN_10;
  GPIO_InitStruct.Mode = GPIO_MODE_OUTPUT_PP;
  GPIO_InitStruct.Pull = GPIO_NOPULL;
  GPIO_InitStruct.Speed = GPIO_SPEED_FREQ_LOW;
  HAL_GPIO_Init(GPIOA, &GPIO_InitStruct);
}

void Error_Handler(void)
{
  /* USER CODE BEGIN Error_Handler */
  /* User can add his own implementation to report the HAL error return state */
  while(1)
  {

    HAL_GPIO_WritePin(GPIOA, GPIO_PIN_12, GPIO_PIN_SET);

  }
  /* USER CODE END Error_Handler */
}

/************************ (C) COPYRIGHT STMicroelectronics *****END OF FILE****/
